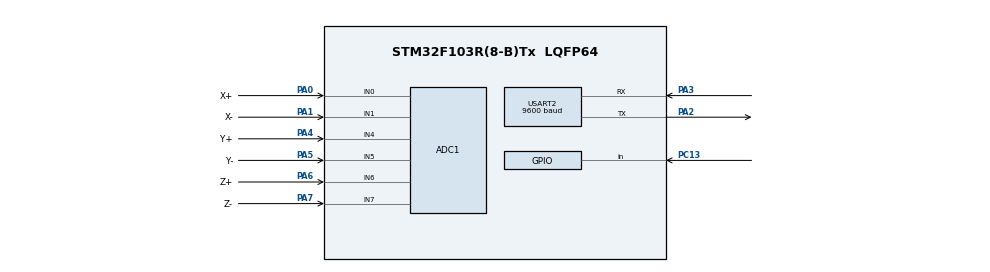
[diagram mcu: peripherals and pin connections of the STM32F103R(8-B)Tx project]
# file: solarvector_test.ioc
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ADC1.Channel-28\#ChannelRegularConversion=ADC_CHANNEL_0
ADC1.Channel-29\#ChannelRegularConversion=ADC_CHANNEL_1
ADC1.Channel-30\#ChannelRegularConversion=ADC_CHANNEL_4
ADC1.Channel-31\#ChannelRegularConversion=ADC_CHANNEL_5
ADC1.Channel-32\#ChannelRegularConversion=ADC_CHANNEL_6
ADC1.Channel-33\#ChannelRegularConversion=ADC_CHANNEL_7
ADC1.ContinuousConvMode=ENABLE
ADC1.DiscontinuousConvMode=DISABLE
ADC1.EnableRegularConversion=ENABLE
ADC1.InjNumberOfConversion=0
ADC1.NbrOfConversion=6
ADC1.NbrOfConversionFlag=1
ADC1.Rank-28\#ChannelRegularConversion=1
ADC1.Rank-29\#ChannelRegularConversion=2
ADC1.Rank-30\#ChannelRegularConversion=3
ADC1.Rank-31\#ChannelRegularConversion=4
ADC1.Rank-32\#ChannelRegularConversion=5
ADC1.Rank-33\#ChannelRegularConversion=6
ADC1.SamplingTime-28\#ChannelRegularConversion=ADC_SAMPLETIME_55CYCLES_5
ADC1.SamplingTime-29\#ChannelRegularConversion=ADC_SAMPLETIME_55CYCLES_5
ADC1.SamplingTime-30\#ChannelRegularConversion=ADC_SAMPLETIME_55CYCLES_5
ADC1.SamplingTime-31\#ChannelRegularConversion=ADC_SAMPLETIME_55CYCLES_5
ADC1.SamplingTime-32\#ChannelRegularConversion=ADC_SAMPLETIME_55CYCLES_5
ADC1.SamplingTime-33\#ChannelRegularConversion=ADC_SAMPLETIME_55CYCLES_5
ADC1.master=1
Dma.ADC1.0.Direction=DMA_PERIPH_TO_MEMORY
Dma.ADC1.0.Instance=DMA1_Channel1
Dma.ADC1.0.MemDataAlignment=DMA_MDATAALIGN_WORD
Dma.ADC1.0.MemInc=DMA_MINC_ENABLE
Dma.ADC1.0.Mode=DMA_CIRCULAR
Dma.ADC1.0.PeriphDataAlignment=DMA_PDATAALIGN_WORD
Dma.ADC1.0.PeriphInc=DMA_PINC_DISABLE
Dma.ADC1.0.Priority=DMA_PRIORITY_LOW
Dma.Request0=ADC1
Mcu.Family=STM32F1
Mcu.Name=STM32F103R(8-B)Tx
Mcu.Package=LQFP64
NVIC.ADC1_2_IRQn=true\:0\:0\:false\:false\:true\:true
NVIC.DMA1_Channel1_IRQn=true\:0\:0\:false\:false\:true\:false
NVIC.PriorityGroup=NVIC_PRIORITYGROUP_4
PA0-WKUP.GPIO_Label=X+
PA0-WKUP.Signal=ADCx_IN0
PA1.GPIO_Label=X-
PA1.Signal=ADCx_IN1
PA2.Mode=Asynchronous
PA2.Signal=USART2_TX
PA3.Mode=Asynchronous
PA3.Signal=USART2_RX
PA4.GPIO_Label=Y+
PA4.Signal=ADCx_IN4
PA5.GPIO_Label=Y-
PA5.Signal=ADCx_IN5
PA6.GPIO_Label=Z+
PA6.Signal=ADCx_IN6
PA7.GPIO_Label=Z-
PA7.Signal=ADCx_IN7
PC13-TAMPER-RTC.Signal=GPIO_Input
ProjectManager.HeapSize=0x400
ProjectManager.StackSize=0x400
ProjectManager.TargetToolchain=MDK-ARM V5
RCC.ADCPresc=RCC_ADCPCLK2_DIV8
RCC.AHBCLKDivider=RCC_SYSCLK_DIV8
RCC.AHBFreq_Value=1000000
RCC.APB1CLKDivider=RCC_HCLK_DIV2
RCC.APB1Freq_Value=500000
RCC.APB1TimFreq_Value=1000000
RCC.APB2Freq_Value=1000000
RCC.APB2TimFreq_Value=1000000
RCC.HCLKFreq_Value=1000000
RCC.PLLMUL=RCC_PLL_MUL7
RCC.RTCClockSelection=RCC_RTCCLKSOURCE_LSE
RCC.SYSCLKFreq_VALUE=8000000
RCC.USBFreq_Value=28000000
SH.ADCx_IN0.0=ADC1_IN0,IN0
SH.ADCx_IN1.0=ADC1_IN1,IN1
SH.ADCx_IN4.0=ADC1_IN4,IN4
SH.ADCx_IN5.0=ADC1_IN5,IN5
SH.ADCx_IN6.0=ADC1_IN6,IN6
SH.ADCx_IN7.0=ADC1_IN7,IN7
USART2.BaudRate=9600
USART2.Mode=MODE_TX_RX
USART2.VirtualMode=VM_ASYNC
VP_SYS_VS_ND.Mode=No_Debug
board=NUCLEO-F103RB

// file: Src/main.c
/* USER CODE BEGIN Header */
/**
  ******************************************************************************
  * @file           : main.c
  * @brief          : Main program body
  ******************************************************************************
  ** This program finds solar vectors and prints information over serial based
	* on which #defines are uncommented below.
	*
	* See the Solar Vector Test SOP.
  ******************************************************************************
  */
/* USER CODE END Header */

#include "main.h"

/* USER CODE BEGIN Includes */
#include <math.h>
#include <stdio.h>
#include <string.h>
#include <SolarVectors.h>
#include <DigitalFilters.h>

/* USER CODE END Includes */

/* USER CODE BEGIN PM */
// #define YAWPITCH_TEST // Uncomment to unit test yaw and pitch function
// #define PRINT_RAW_VALS
// #define PRINT_SOLAR_VECTOR
#define PRINT_YAWPITCH

#define ADC_CHANNEL_XP 0
#define ADC_CHANNEL_XN 1
#define ADC_CHANNEL_YP 2
#define ADC_CHANNEL_YN 3
#define ADC_CHANNEL_ZP 4
#define ADC_CHANNEL_ZN 5
#define NUM_ADC_CHANNELS 6
#define MOVING_AVG_LENGTH 10

#define PI 3.1416

/* USER CODE END PM */

ADC_HandleTypeDef hadc1;
DMA_HandleTypeDef hdma_adc1;

UART_HandleTypeDef huart2;

/* USER CODE BEGIN PV */

ADC_ChannelConfTypeDef sConfig = {0};
uint32_t adc_data[NUM_ADC_CHANNELS];
float sv_raw[NUM_ADC_CHANNELS];

/* USER CODE END PV */

void SystemClock_Config(void);
static void MX_GPIO_Init(void);
static void MX_DMA_Init(void);
static void MX_USART2_UART_Init(void);
static void MX_ADC1_Init(void);

int main(void)
{

  /* MCU Configuration--------------------------------------------------------*/

  /* Reset of all peripherals, Initializes the Flash interface and the Systick. */
  HAL_Init();

  /* Configure the system clock */
  SystemClock_Config();

  /* Initialize all configured peripherals */
  MX_GPIO_Init();
  MX_DMA_Init();
  MX_USART2_UART_Init();
  MX_ADC1_Init();
  /* USER CODE BEGIN 2 */

	char transmit[200];

	#ifdef YAWPITCH_TEST // Unit testing
	int num_tests = 7;
	double x_components[] = {1,		0.7071,	 -0.7071,   0.7071,  -0.7071,  0.7071,        0};
	double y_components[] = {0, 	0.7071,		0.7071,  -0.7071,  -0.7071,       0,  -0.7071};
	double z_components[] = {0, 			 0, 			 0, 			 0, 			 0,  0.7071,  -0.7071};

	double desired_yaw[] =  {0, 			45, 		 135,			 -45,			-135,				0,			-90};
	double desired_pitch[] = {0,			 0,				 0,				 0,				 0, 		 45,			-45};

	for(int i = 0;i < num_tests;i++) {
		Matrix v = make3x1Vector(x_components[i], y_components[i], z_components[i]);
		matrixScale(v, 1.0/vectorNorm(v));
		char transmit[50];
		printSolarVector(v, transmit);
		HAL_UART_Transmit(&huart2, (uint8_t*)transmit, strlen(transmit), 50);
		sprintf(transmit, "Desired:\r\nyaw: %3.1f pitch: %3.1f\r\n\r\n", desired_yaw[i], desired_pitch[i]);
		HAL_UART_Transmit(&huart2, (uint8_t*)transmit, strlen(transmit), 50);
	}

	while(1);
	#endif

	HAL_ADC_Start_DMA(&hadc1, adc_data, NUM_ADC_CHANNELS); // Start ADC in DMA mode

	sprintf(transmit, "Finished init\r\n");
	HAL_UART_Transmit(&huart2, (uint8_t*)transmit, strlen(transmit), 20);

	// See the Attitude Control System document for info on the body reference frame and axes
	double volts_xp, volts_xn, volts_yp, volts_yn, volts_zp, volts_zn; // Positive and negative raw current values for each axis

	MovingAvgFilter filter = newMovingAvgFilter(NUM_ADC_CHANNELS, MOVING_AVG_LENGTH);

	Matrix solar_vector = newMatrix(3, 1); // Make a new column vector Matrix for the solar vector

  /* USER CODE END 2 */

  /* Infinite loop */
  /* USER CODE BEGIN WHILE */
  while (1)
  {
		// Read ADC
		for(int i = 0;i < NUM_ADC_CHANNELS;i++) {
			sv_raw[i] = ADC_TO_VOLTS(adc_data[i]);
		}
		runMovingAvgFilter(filter, sv_raw); // Moving average solar vector readings

		#ifdef PRINT_RAW_VALS
		// Read data and convert to volts
		volts_xp = sv_raw[ADC_CHANNEL_XP]*XP_SCALE;
		volts_xn = sv_raw[ADC_CHANNEL_XN]*XN_SCALE;
		volts_yp = sv_raw[ADC_CHANNEL_YP]*YP_SCALE;
		volts_yn = sv_raw[ADC_CHANNEL_YN]*YN_SCALE;
		volts_zp = sv_raw[ADC_CHANNEL_ZP]*ZP_SCALE;
		volts_zn = sv_raw[ADC_CHANNEL_ZN]*ZN_SCALE;

		// Print x values
		sprintf(transmit, "xp: %2.4f xn: %2.4f\r\n", volts_xp, volts_xn);
		HAL_UART_Transmit(&huart2, (uint8_t*)transmit, strlen(transmit), 40);

		// Print y values
		sprintf(transmit, "yp: %2.4f yn: %2.4f\r\n", volts_yp, volts_yn);
		HAL_UART_Transmit(&huart2, (uint8_t*)transmit, strlen(transmit), 40);

		// Print z values
		sprintf(transmit, "zp: %2.4f zn: %2.4f\r\n", volts_zp, volts_zn);
		HAL_UART_Transmit(&huart2, (uint8_t*)transmit, strlen(transmit), 40);
		#endif

		// Calculate solar vector
		SV_Status sv_return = findSolarVector(sv_raw, 5, solar_vector);

		if(sv_return == SV_FOUND) { // Check if a valid solar vector was found
			#ifdef PRINT_SOLAR_VECTOR
			// Print solar vector over serial using the Matrix library command;
			printMatrix(solar_vector, transmit);
			HAL_UART_Transmit(&huart2, (uint8_t*)transmit, strlen(transmit), 40);
			#endif
			#ifdef PRINT_YAWPITCH
			// Print solar vector over serial using the SolarVector library command
			printSolarVector(solar_vector, transmit);
			HAL_UART_Transmit(&huart2, (uint8_t*)transmit, strlen(transmit), 40);
			#endif
		}
		else if(sv_return == SV_NOTFOUND){
			sprintf(transmit, "Solar vector indeterminate!\r\n");
			HAL_UART_Transmit(&huart2, (uint8_t*)transmit, strlen(transmit), 30);
		}
		else {
			sprintf(transmit, "Dark detected!\r\n");
			HAL_UART_Transmit(&huart2, (uint8_t*)transmit, strlen(transmit), 20);
		}

		sprintf(transmit, "\r\n");
		HAL_UART_Transmit(&huart2, (uint8_t*)transmit, strlen(transmit), 30);

		HAL_Delay(100);

    /* USER CODE END WHILE */

  }
}

void SystemClock_Config(void)
{
  RCC_OscInitTypeDef RCC_OscInitStruct = {0};
  RCC_ClkInitTypeDef RCC_ClkInitStruct = {0};
  RCC_PeriphCLKInitTypeDef PeriphClkInit = {0};

  /**Initializes the CPU, AHB and APB busses clocks
  */
  RCC_OscInitStruct.OscillatorType = RCC_OSCILLATORTYPE_HSI;
  RCC_OscInitStruct.HSIState = RCC_HSI_ON;
  RCC_OscInitStruct.HSICalibrationValue = RCC_HSICALIBRATION_DEFAULT;
  RCC_OscInitStruct.PLL.PLLState = RCC_PLL_NONE;
  if (HAL_RCC_OscConfig(&RCC_OscInitStruct) != HAL_OK)
  {
    Error_Handler();
  }
  /**Initializes the CPU, AHB and APB busses clocks
  */
  RCC_ClkInitStruct.ClockType = RCC_CLOCKTYPE_HCLK|RCC_CLOCKTYPE_SYSCLK
                              |RCC_CLOCKTYPE_PCLK1|RCC_CLOCKTYPE_PCLK2;
  RCC_ClkInitStruct.SYSCLKSource = RCC_SYSCLKSOURCE_HSI;
  RCC_ClkInitStruct.AHBCLKDivider = RCC_SYSCLK_DIV1;
  RCC_ClkInitStruct.APB1CLKDivider = RCC_HCLK_DIV2;
  RCC_ClkInitStruct.APB2CLKDivider = RCC_HCLK_DIV1;

  if (HAL_RCC_ClockConfig(&RCC_ClkInitStruct, FLASH_LATENCY_0) != HAL_OK)
  {
    Error_Handler();
  }
  PeriphClkInit.PeriphClockSelection = RCC_PERIPHCLK_ADC;
  PeriphClkInit.AdcClockSelection = RCC_ADCPCLK2_DIV8;
  if (HAL_RCCEx_PeriphCLKConfig(&PeriphClkInit) != HAL_OK)
  {
    Error_Handler();
  }
}

static void MX_ADC1_Init(void)
{

  ADC_ChannelConfTypeDef sConfig = {0};

  /**Common config
  */
  hadc1.Instance = ADC1;
  hadc1.Init.ScanConvMode = ADC_SCAN_ENABLE;
  hadc1.Init.ContinuousConvMode = ENABLE;
  hadc1.Init.DiscontinuousConvMode = DISABLE;
  hadc1.Init.ExternalTrigConv = ADC_SOFTWARE_START;
  hadc1.Init.DataAlign = ADC_DATAALIGN_RIGHT;
  hadc1.Init.NbrOfConversion = 6;
  if (HAL_ADC_Init(&hadc1) != HAL_OK)
  {
    Error_Handler();
  }
  /**Configure Regular Channel
  */
  sConfig.Channel = ADC_CHANNEL_0;
  sConfig.Rank = ADC_REGULAR_RANK_1;
  sConfig.SamplingTime = ADC_SAMPLETIME_55CYCLES_5;
  if (HAL_ADC_ConfigChannel(&hadc1, &sConfig) != HAL_OK)
  {
    Error_Handler();
  }
  /**Configure Regular Channel
  */
  sConfig.Channel = ADC_CHANNEL_1;
  sConfig.Rank = ADC_REGULAR_RANK_2;
  if (HAL_ADC_ConfigChannel(&hadc1, &sConfig) != HAL_OK)
  {
    Error_Handler();
  }
  /**Configure Regular Channel
  */
  sConfig.Channel = ADC_CHANNEL_4;
  sConfig.Rank = ADC_REGULAR_RANK_3;
  if (HAL_ADC_ConfigChannel(&hadc1, &sConfig) != HAL_OK)
  {
    Error_Handler();
  }
  /**Configure Regular Channel
  */
  sConfig.Channel = ADC_CHANNEL_5;
  sConfig.Rank = ADC_REGULAR_RANK_4;
  if (HAL_ADC_ConfigChannel(&hadc1, &sConfig) != HAL_OK)
  {
    Error_Handler();
  }
  /**Configure Regular Channel
  */
  sConfig.Channel = ADC_CHANNEL_6;
  sConfig.Rank = ADC_REGULAR_RANK_5;
  if (HAL_ADC_ConfigChannel(&hadc1, &sConfig) != HAL_OK)
  {
    Error_Handler();
  }
  /**Configure Regular Channel
  */
  sConfig.Channel = ADC_CHANNEL_7;
  sConfig.Rank = ADC_REGULAR_RANK_6;
  if (HAL_ADC_ConfigChannel(&hadc1, &sConfig) != HAL_OK)
  {
    Error_Handler();
  }

}

static void MX_USART2_UART_Init(void)
{

  huart2.Instance = USART2;
  huart2.Init.BaudRate = 115200;
  huart2.Init.WordLength = UART_WORDLENGTH_8B;
  huart2.Init.StopBits = UART_STOPBITS_1;
  huart2.Init.Parity = UART_PARITY_NONE;
  huart2.Init.Mode = UART_MODE_TX_RX;
  huart2.Init.HwFlowCtl = UART_HWCONTROL_NONE;
  huart2.Init.OverSampling = UART_OVERSAMPLING_16;
  if (HAL_UART_Init(&huart2) != HAL_OK)
  {
    Error_Handler();
  }

}

static void MX_DMA_Init(void)
{
  /* DMA controller clock enable */
  __HAL_RCC_DMA1_CLK_ENABLE();

  /* DMA interrupt init */
  /* DMA1_Channel1_IRQn interrupt configuration */
  HAL_NVIC_SetPriority(DMA1_Channel1_IRQn, 0, 0);
  HAL_NVIC_EnableIRQ(DMA1_Channel1_IRQn);

}

static void MX_GPIO_Init(void)
{
  GPIO_InitTypeDef GPIO_InitStruct = {0};

  /* GPIO Ports Clock Enable */
  __HAL_RCC_GPIOC_CLK_ENABLE();
  __HAL_RCC_GPIOA_CLK_ENABLE();

  /*Configure GPIO pin : PC13 */
  GPIO_InitStruct.Pin = GPIO_PIN_13;
  GPIO_InitStruct.Mode = GPIO_MODE_INPUT;
  GPIO_InitStruct.Pull = GPIO_NOPULL;
  HAL_GPIO_Init(GPIOC, &GPIO_InitStruct);

}

void Error_Handler(void)
{
}

/************************ (C) COPYRIGHT STMicroelectronics *****END OF FILE****/
